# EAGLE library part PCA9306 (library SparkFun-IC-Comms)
Bidirectional I2C level shifter Not compatible with all available part number pinout schemes- DOUBLE CHECK!!! Variants PCA9306DC and PSOP-8 are EOL. If your part has VREF as pin 1 then this is your variant. VSSOP_8PIN is not EOL. Datasheet SparkFun Products SparkFun Inventor's Kit for RedBot (ROB-12649) SparkFun RedBot Basic Kit (ROB-13166) SparkFun Level Translator Breakout - PCA9306 (BOB-11955) SparkFun Block for Intel Edison - ADC (DEV-13770) SparkFun Block for Intel® Edison - Raspberry Pi B (DEV-13044) SparkFun RedBot Sensor - Accelerometer (SEN-12589)

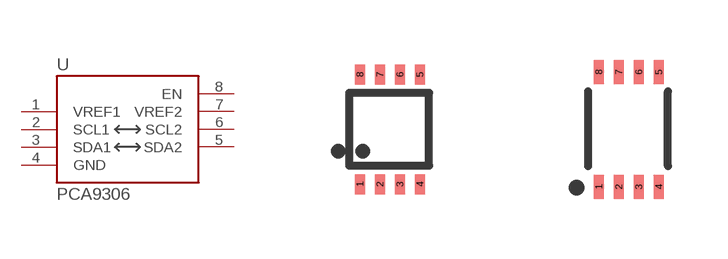
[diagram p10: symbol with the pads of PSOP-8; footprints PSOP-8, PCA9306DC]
Designator prefix U

## PCA9306 (PROD_ID: IC-10023; VALUE: PCA9306)  [PSOP-8]
1  VREF1  pwr
2  SCL1
3  SDA1
4  GND  pwr
5  SDA2
6  SCL2
7  VREF2  pwr
8  EN  in

## PCA9306PCA9306DC (PROD_ID: IC-10023; VALUE: PCA9306)  [PCA9306DC]
Pads as for PSOP-8

## PCA9306VSSOP_8PIN (PROD_ID: IC-14450)  [VSSOP_8PIN]
P1  GND  pwr
P2  VREF1  pwr
P3  SCL1
P4  SDA1
P5  SDA2
P6  SCL2
P7  VREF2  pwr
P8  EN  in

## Footprint PSOP-8 (pad centres in mm)
PSOP-8 Specifications: Pin count:8 Example device(s): PCA9306
smd 0.25 x 0.5: 1 -0.73,-1.37; 2 -0.23,-1.37; 3 0.27,-1.37; 4 0.77,-1.37; 5 0.77,1.38; 6 0.27,1.38; 7 -0.23,1.38; 8 -0.73,1.38

## Footprint PCA9306DC (pad centres in mm)
PCA9306DC 1:1 package. Specifications: Pin count: 8 Example device(s): PCA9306
smd 0.25 x 0.602: 1 -0.73,-1.446; 2 -0.23,-1.446; 3 0.27,-1.446; 4 0.77,-1.446; 5 0.77,1.431; 6 0.27,1.431; 7 -0.23,1.431; 8 -0.73,1.431

## Footprint VSSOP_8PIN (pad centres in mm)
VSSOP 8-Pin Physical Characteristics Lead to Lead SIze: 3.2 x 2.1 mm Body Size: 2.1 x 2.4 x .9 mm Lead: .25 x .8 mm Pitch: .5 mm
smd 0.8 x 0.3: P1 -1.57,0.734; P2 -1.57,0.234; P3 -1.57,-0.266; P4 -1.57,-0.766; P5 1.53,-0.766; P6 1.53,-0.266; P7 1.53,0.234; P8 1.53,0.734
